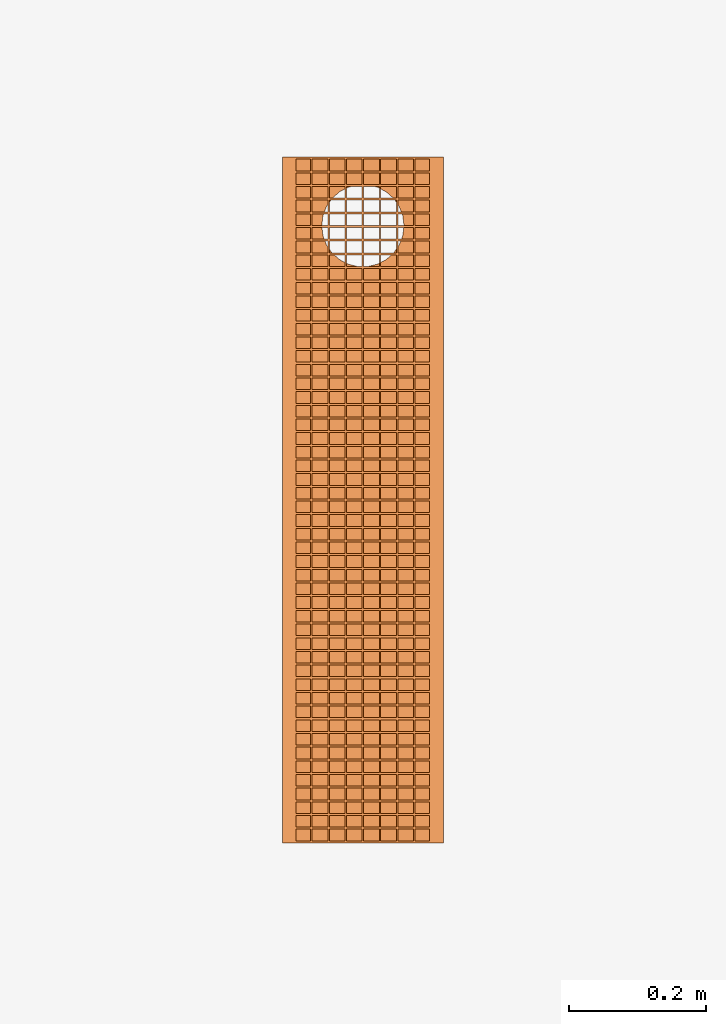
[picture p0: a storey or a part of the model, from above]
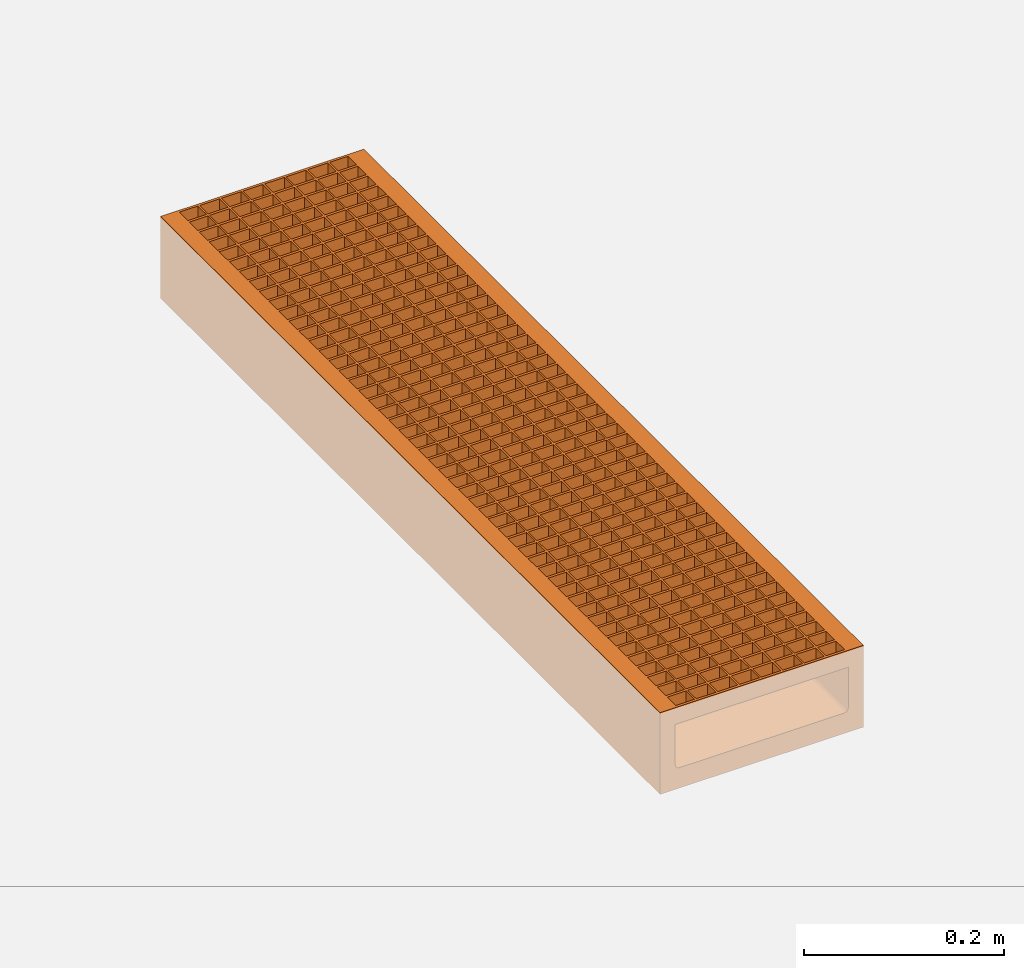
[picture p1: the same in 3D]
Properties of the parts of a building model (IFC2X3)

# File
Description: ViewDefinition [CoordinationView]
File name: 24217 - No 0100V Shallow Depth Channel - 1000mm LG - Invert Depth 75mm.ifc
Time: 2013-10-16T12:50:55
Written by: Autodesk Revit 2013
Made in: 20120221_2030(x64)

# IfcProject, Project Number
LongName: Project Name; Phase: Project Status

# IfcSite, Default
RefLatitude: 42, 21, 30, 344238; RefLongitude: -71, -3, -35, -194702; RefElevation: 0 mm

# IfcBuilding
Pset_BuildingCommon - NumberOfStoreys: 1
Other - Project Name: Project Name; Project Issue Date: Issue Date; Project Number: Project Number; Project Address: ## Street City, State Zip; Client Name: Owner; Project Status: Project Status

# IfcBuildingStorey, Level 1
LongName: Level 1; Elevation: 0 mm
Constraints - Elevation Base: 0; Elevation: 0 mm
Graphics - Line Pattern: Center; Symbol: M_Level Head - Circle: M_Level Head - Circle; Symbol at End 1 Default: no; Line Weight: 1; Symbol at End 2 Default: yes; Color: 0
Identity Data - Structural: no; Building Story: yes; Name: Level 1
Dimensions - Computation Height: 0 mm

# IfcBuildingElementProxy: 24217 - No 0100V Shallow Depth Channel - 1000mm LG - Invert Depth 75mm, Civil-Drainage-Channel-ACO-MultiDrain-M200DS-Channel-System:24217 - No 0100V Shallow Depth Channel - 1000mm LG - Invert Depth 75mm:24217 - No 0100V Shallow Depth Channel - 1000mm LG - Invert Depth 75mm:1152340
In: Level 1
Material: Plastic, Opaque Black, Vienite® Synthetic Resin Concrete
Model Properties - Grating Product code 13448: Load Class C250 - Mesh Stainless Steel Grade 304 13448DL 1000mm long - 23x17mm slot - Intake area 154100mm²/m - 12.0kg; End Cap Product code 23219: No 306 Universal End Cap - 235mm wide x 365mm long - Spigot Ø160mm x 75mm long - Silver - Polypropylene - 0.4kg; Grating Product code 13449: Load Class C250 - Mesh Stainless Steel Grade 304 13449DL 500mm long - 23x17mm slot - Intake area 154100mm²/m - 6.0kg
Construction - 13449 - Grating - Mesh - Stainless Steel - 500mm Long: no; 23219 - Universal Endcap (Female End): no; 13448 - Grating - Mesh - Stainless Steel - 1000mm Long: no; 23219 - Universal Endcap (Male End): no; Constant Depth Channel_500: no; Constant Depth Channel_1000: no; Grating_1000mm: yes; 23410_Sump Unit: no; Shallow Depth Channel: no; Grating_500mm: no; Shallow Depth Channel with seal: yes
Constraints - Level: Level: Level 1; Moves With Nearby Elements: no
Phasing - Phase Created: New Construction
Dimensions - Custom_Value_Length: 0 mm; FloorCut_Length: -1000 mm; Length: 1000 mm; Volume: 9274283 mm3; EndCap Position: 1000 mm; InvDepth: 240 mm; FloorCut_Width: 235 mm; FloorCut_HorPosition: 117.5 mm; FloorCut_Depth: 100 mm; EndCap_Height: 100 mm; Depth: 365 mm
Pset_BuildingElementProxyCommon - Reference: 24217 - No 0100V Shallow Depth Channel - 1000mm LG - Invert Depth 75mm
General - TagNumber: 0; SerialNumber: 0
Identity Data - Address: ACO Business Park, Hitchin Road, Shefford, Bedfordshire, United Kingdom SG17 5TE; Telephone: +44 (0)1462 816666; Maintenance guidelines: http://www.aco.co.uk/download.php?id=173; OmniClass Number: 23.70.50.24; Assembly Code: D2040; OmniClass Title: Rainwater Removal; Watermark 2: This file is water marked and users are prohibited to reproduce, adapt, distribute this information; Fax: +44 (0)1462 815895; Product Page URL: http://www.aco.co.uk/product_detail.php?id=15; Model: ACO MultiDrain MD - M200DS; Cost: 0; Price: POA - contact ACO; Type Comments: ACO MultiDrain M200DS 0100V Shallow Constant Depth Channel 1000mm Long; Watermarked With: BIM Manager Premium Suite; Product brochure: http://www.aco.co.uk/download.php?id=173; e-mail Technical: technical@aco.co.uk; Installation guidelines: http://www.aco.co.uk/download.php?id=173; e-mail Sales: customersupport@aco.co.uk; Assembly Description: Rain Water Drainage; Watermarked By: www.aco.co.uk; URL: www.aco.co.uk; Product Code: 24217; Watermark 1: This file is the property of ACO Technologies PLC; Model Description: Channel drainage system; Manufacturer: ACO Technologies plc - ACO Water Management Division
Data - Channel C.S.A: 0.01m²; Concrete Surround Volume - Load Class D 400 - Concrete Pavement: 0.17m³/m; Invert Depth: 75mm; Product Dimensions: 1000mm x 235mm x 100mm (LxWxH); ACO Hydraulic Design Software: http://www.acodesign.co.uk; Concrete Surround Volume - Load Class B 125 - C 250 - Concrete Pavement: 0.11m³/m; Product Weight: 18.7 Kg; Installation - Concrete Grade: Refer to brochure; Concrete Surround Volume - Load Class A 15 - Concrete Pavement: 0.06m³/m; Product Standard: BS EN 1433:2002, CE marked; Load Class: A 15 - D 400; Hydraulic Performance: http://www.aco.co.uk/download.php?id=173
Green Building Properties - Edge Rail Recycled Material Content: Between 40% - 90%; Channel Recyclable: Fully recyclable; Edge Rail Recyclable: Fully recyclable; Channel Recycled Material Content: 20% minimum
Materials and Finishes - Edge Rail Material: Stainless Steel Grade 304; Channel Colour: Brown; Edge Rail Colour: Self; Channel Material: Vienite® Synthetic Resin Concrete
Other - CreatedBy: www.aco.co.uk; Revision: 1

# IfcOpeningElement: Opening, Civil-Drainage-Channel-ACO-MultiDrain-M200DS-Channel-System:24217 - No 0100V Shallow Depth Channel - 1000mm LG - Invert Depth 75mm:24217 - No 0100V Shallow Depth Channel - 1000mm LG - Invert Depth 75mm:1152340:1
In: Level 1
Model Properties - Grating Product code 13448: Load Class C250 - Mesh Stainless Steel Grade 304 13448DL 1000mm long - 23x17mm slot - Intake area 154100mm²/m - 12.0kg; End Cap Product code 23219: No 306 Universal End Cap - 235mm wide x 365mm long - Spigot Ø160mm x 75mm long - Silver - Polypropylene - 0.4kg; Grating Product code 13449: Load Class C250 - Mesh Stainless Steel Grade 304 13449DL 500mm long - 23x17mm slot - Intake area 154100mm²/m - 6.0kg
Construction - 13449 - Grating - Mesh - Stainless Steel - 500mm Long: no; 23219 - Universal Endcap (Female End): no; 13448 - Grating - Mesh - Stainless Steel - 1000mm Long: no; 23219 - Universal Endcap (Male End): no; Constant Depth Channel_500: no; Constant Depth Channel_1000: no; Grating_1000mm: yes; 23410_Sump Unit: no; Shallow Depth Channel: no; Grating_500mm: no; Shallow Depth Channel with seal: yes
Constraints - Level: Level: Level 1; Moves With Nearby Elements: no
Phasing - Phase Created: New Construction
Dimensions - Custom_Value_Length: 0 mm; FloorCut_Length: -1000 mm; Length: 1000 mm; Volume: 9274283 mm3; EndCap Position: 1000 mm; InvDepth: 240 mm; FloorCut_Width: 235 mm; FloorCut_HorPosition: 117.5 mm; FloorCut_Depth: 100 mm; EndCap_Height: 100 mm; Depth: 365 mm
General - TagNumber: 0; SerialNumber: 0
Identity Data - Address: ACO Business Park, Hitchin Road, Shefford, Bedfordshire, United Kingdom SG17 5TE; Telephone: +44 (0)1462 816666; Maintenance guidelines: http://www.aco.co.uk/download.php?id=173; OmniClass Number: 23.70.50.24; Assembly Code: D2040; OmniClass Title: Rainwater Removal; Watermark 2: This file is water marked and users are prohibited to reproduce, adapt, distribute this information; Fax: +44 (0)1462 815895; Product Page URL: http://www.aco.co.uk/product_detail.php?id=15; Model: ACO MultiDrain MD - M200DS; Cost: 0; Price: POA - contact ACO; Type Comments: ACO MultiDrain M200DS 0100V Shallow Constant Depth Channel 1000mm Long; Watermarked With: BIM Manager Premium Suite; Product brochure: http://www.aco.co.uk/download.php?id=173; e-mail Technical: technical@aco.co.uk; Installation guidelines: http://www.aco.co.uk/download.php?id=173; e-mail Sales: customersupport@aco.co.uk; Assembly Description: Rain Water Drainage; Watermarked By: www.aco.co.uk; URL: www.aco.co.uk; Product Code: 24217; Watermark 1: This file is the property of ACO Technologies PLC; Model Description: Channel drainage system; Manufacturer: ACO Technologies plc - ACO Water Management Division
Data - Channel C.S.A: 0.01m²; Concrete Surround Volume - Load Class D 400 - Concrete Pavement: 0.17m³/m; Invert Depth: 75mm; Product Dimensions: 1000mm x 235mm x 100mm (LxWxH); ACO Hydraulic Design Software: http://www.acodesign.co.uk; Concrete Surround Volume - Load Class B 125 - C 250 - Concrete Pavement: 0.11m³/m; Product Weight: 18.7 Kg; Installation - Concrete Grade: Refer to brochure; Concrete Surround Volume - Load Class A 15 - Concrete Pavement: 0.06m³/m; Product Standard: BS EN 1433:2002, CE marked; Load Class: A 15 - D 400; Hydraulic Performance: http://www.aco.co.uk/download.php?id=173
Green Building Properties - Edge Rail Recycled Material Content: Between 40% - 90%; Channel Recyclable: Fully recyclable; Edge Rail Recyclable: Fully recyclable; Channel Recycled Material Content: 20% minimum
Materials and Finishes - Edge Rail Material: Stainless Steel Grade 304; Channel Colour: Brown; Edge Rail Colour: Self; Channel Material: Vienite® Synthetic Resin Concrete
Other - CreatedBy: www.aco.co.uk; Revision: 1

# IfcOpeningElement: Recess
In: Level 1
Constraints - Related to Mass: no; Room Bounding: yes; Height Offset From Level: 0 mm; Level: Level: Level 1
Dimensions - Volume: 9976500000 mm3; Thickness: 400 mm; Area: 25000000 mm2; Perimeter: 20000 mm
Phasing - Phase Created: New Construction
Structural - Enable Analytical Model: no; Structural: no
Analytical Properties - Heat Transfer Coefficient (U): 2.0925; Roughness: 1; Thermal Resistance (R): 0.477897; Absorptance: 0.1; Thermal mass: 543920
Graphics - Coarse Scale Fill Color: 0
Construction - Default Thickness: 400 mm; Function: 0
Materials and Finishes - Structural Material: Earth

# IfcSlab: Floor:Generic Floor - 400mm, Floor:Generic Floor - 400mm:193825
In: Level 1
PredefinedType: FLOOR; Material: Earth 400 mm
Constraints - Related to Mass: no; Room Bounding: yes; Height Offset From Level: 0 mm; Level: Level: Level 1
Dimensions - Volume: 9976500000 mm3; Thickness: 400 mm; Area: 25000000 mm2; Perimeter: 20000 mm
Phasing - Phase Created: New Construction
Structural - Enable Analytical Model: no; Structural: no
Pset_SlabCommon - Reference: Generic Floor - 400mm; IsExternal: no; LoadBearing: yes
Analytical Properties - Heat Transfer Coefficient (U): 2.0925; Roughness: 1; Thermal Resistance (R): 0.477897; Absorptance: 0.1; Thermal mass: 543920
Graphics - Coarse Scale Fill Color: 0
Construction - Default Thickness: 400 mm; Function: 0
Materials and Finishes - Structural Material: Earth
